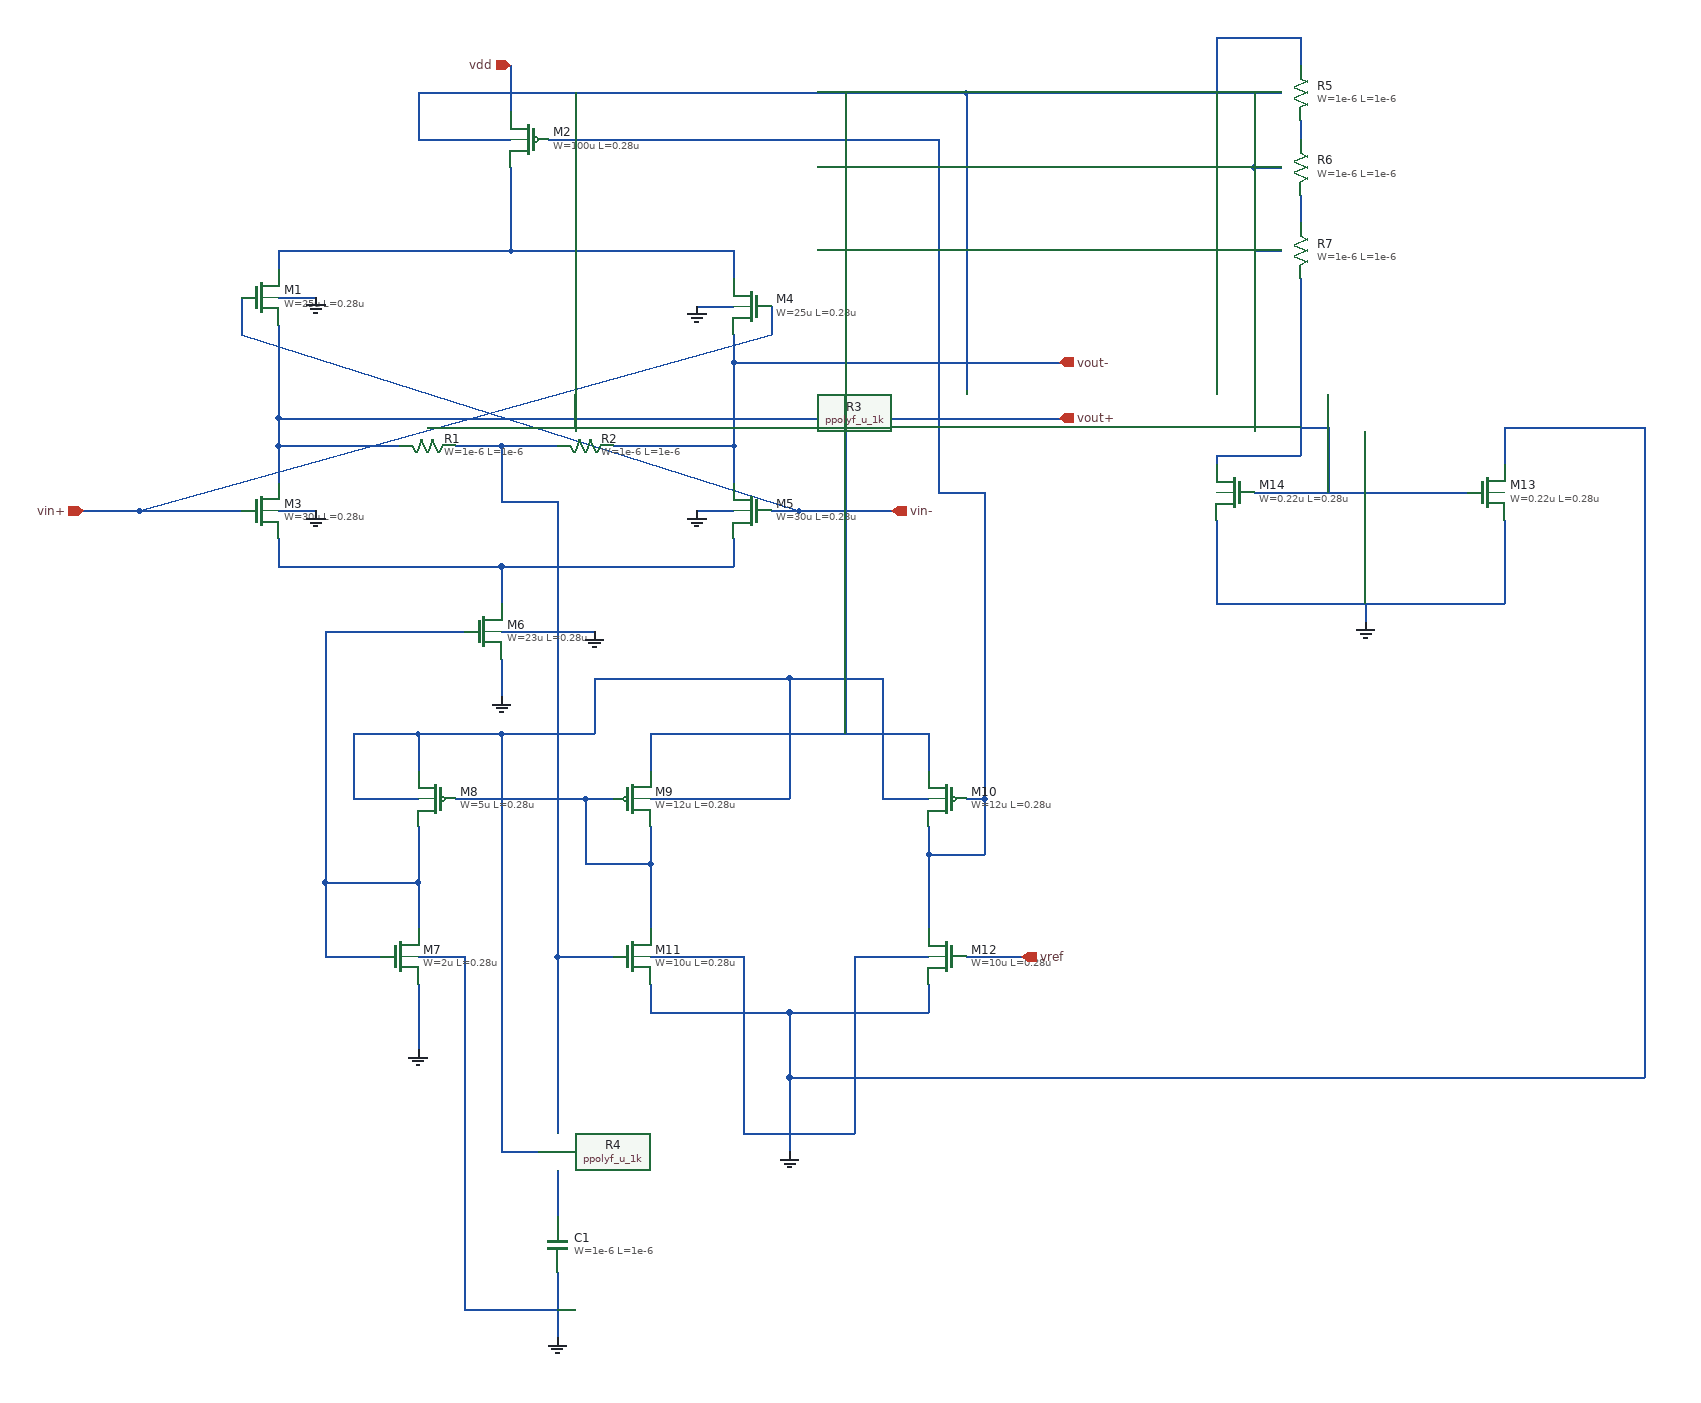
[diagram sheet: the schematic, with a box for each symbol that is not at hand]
v {xschem version=3.4.8RC file_version=1.3}
G {}
K {}
V {}
S {}
F {}
E {}
P 4 1 -660 130 {}
N -940 -600 -940 -560 {lab=vout+}
N -450 -600 -450 -560 {lab=vout-}
N -940 -810 -940 -790 {lab=#net1}
N -690 -810 -450 -810 {lab=#net1}
N -450 -810 -450 -780 {lab=#net1}
N -940 -500 -940 -470 {lab=#net2}
N -700 -470 -450 -470 {lab=#net2}
N -450 -500 -450 -470 {lab=#net2}
N -940 -600 -810 -600 {lab=vout+}
N -700 -600 -640 -600 {lab=#net3}
N -750 -600 -700 -600 {lab=#net3}
N -580 -600 -450 -600 {lab=vout-}
N -450 -690 -100 -690 {lab=vout-}
N -940 -630 -100 -630 {lab=vout+}
N -690 -900 -690 -810 {lab=#net1}
N -690 -1010 -690 -960 {lab=vdd}
N -700 -470 -700 -430 {lab=#net2}
N -700 -370 -700 -330 {lab=0}
N -890 -400 -740 -400 {lab=#net4}
N -890 -130 -890 -50 {lab=#net4}
N -790 -130 -790 -80 {lab=#net4}
N -610 -220 -580 -220 {lab=#net5}
N -540 -290 -540 -250 {lab=vdd}
N -400 -290 -240 -290 {lab=vdd}
N -240 -290 -240 -250 {lab=vdd}
N -540 -150 -540 -80 {lab=#net5}
N -240 -160 -240 -80 {lab=#net6}
N -540 -20 -540 10 {lab=0}
N -390 10 -240 10 {lab=0}
N -240 -20 -240 10 {lab=0}
N -640 -50 -640 20 {lab=#net3}
N -640 -50 -580 -50 {lab=#net3}
N -640 -540 -640 -50 {lab=#net3}
N -700 -540 -640 -540 {lab=#net3}
N -700 -600 -700 -540 {lab=#net3}
N -790 -20 -790 50 {lab=0}
N -200 -50 -140 -50 {lab=vref}
N -390 110 -390 160 {lab=0}
N -890 -50 -830 -50 {lab=#net4}
N -390 10 -390 50 {lab=0}
N -200 -220 -180 -220 {lab=#net6}
N -240 -160 -180 -160 {lab=#net6}
N -180 -220 -180 -160 {lab=#net6}
N -650 -930 -230 -930 {lab=#net6}
N -180 -550 -180 -220 {lab=#net6}
N -230 -550 -180 -550 {lab=#net6}
N -230 -930 -230 -550 {lab=#net6}
N -410 -750 -410 -720 {lab=vin+}
N -1090 -530 -410 -720 {lab=vin+}
N -1090 -530 -980 -530 {lab=vin+}
N -1150 -530 -1090 -530 {lab=vin+}
N -980 -760 -980 -720 {lab=vin-}
N -980 -720 -380 -530 {lab=vin-}
N -410 -530 -380 -530 {lab=vin-}
N -380 -530 -280 -530 {lab=vin-}
N -940 -530 -900 -530 {lab=0}
N -940 -760 -900 -760 {lab=0}
N -490 -750 -450 -750 {lab=0}
N -490 -530 -450 -530 {lab=0}
N -700 -400 -660 -400 {lab=0}
N -790 -290 -790 -250 {lab=vdd}
N -610 -220 -610 -150 {lab=#net5}
N -610 -150 -540 -150 {lab=#net5}
N -890 -130 -790 -130 {lab=#net4}
N -940 -630 -940 -600 {lab=vout+}
N -450 -690 -450 -600 {lab=vout-}
N -450 -720 -450 -690 {lab=vout-}
N -940 -730 -940 -630 {lab=vout+}
N -940 -810 -690 -810 {lab=#net1}
N -940 -470 -700 -470 {lab=#net2}
N -540 -290 -400 -290 {lab=vdd}
N -540 10 -390 10 {lab=0}
N -240 -190 -240 -160 {lab=#net6}
N -750 -220 -610 -220 {lab=#net5}
N -540 -190 -540 -150 {lab=#net5}
N -890 -400 -890 -130 {lab=#net4}
N -790 -190 -790 -130 {lab=#net4}
N -640 20 -640 80 {lab=#net3}
N -640 180 -640 230 {lab=#net7}
N -640 290 -640 360 {lab=0}
N -690 -980 -210 -980 {lab=vdd}
N -210 -980 -200 -980 {lab=vdd}
N -200 -980 -200 -660 {lab=vdd}
N -790 -980 -690 -980 {lab=vdd}
N -790 -980 -790 -930 {lab=vdd}
N -790 -930 -690 -930 {lab=vdd}
N -790 -50 -740 -50 {lab=0}
N -740 -50 -740 330 {lab=0}
N -740 330 -640 330 {lab=0}
N -330 -980 -330 -290 {lab=vdd}
N -540 -220 -390 -220 {lab=vdd}
N -390 -350 -390 -220 {lab=vdd}
N -390 -350 -330 -350 {lab=vdd}
N -290 -220 -240 -220 {lab=vdd}
N -290 -350 -290 -220 {lab=vdd}
N -330 -350 -290 -350 {lab=vdd}
N -700 -290 -700 110 {lab=vdd}
N -700 -290 -600 -290 {lab=vdd}
N -600 -350 -600 -290 {lab=vdd}
N -600 -350 -390 -350 {lab=vdd}
N -540 -50 -440 -50 {lab=0}
N -440 -50 -440 140 {lab=0}
N -440 140 -390 140 {lab=0}
N -390 140 -320 140 {lab=0}
N -320 -50 -320 140 {lab=0}
N -320 -50 -240 -50 {lab=0}
N -790 -290 -700 -290 {lab=vdd}
N -660 -400 -600 -400 {lab=0}
N -860 -220 -790 -220 {lab=vdd}
N -860 -290 -860 -220 {lab=vdd}
N -860 -290 -790 -290 {lab=vdd}
N -200 -980 140 -980 {lab=vdd}
N 70 -1040 70 -980 {lab=vdd}
N 70 -1040 160 -1040 {lab=vdd}
N 160 -1040 160 -1010 {lab=vdd}
N 110 -550 340 -550 {lab=#net8}
N 70 -590 150 -590 {lab=#net8}
N 70 -590 70 -580 {lab=#net8}
N 190 -620 190 -550 {lab=#net8}
N 70 -520 70 -430 {lab=0}
N 70 -430 380 -430 {lab=0}
N 380 -520 380 -430 {lab=0}
N 230 -430 230 -410 {lab=0}
N 380 -620 380 -590 {lab=0}
N 380 -620 520 -620 {lab=0}
N -280 80 530 80 {lab=0}
N -390 80 -280 80 {lab=0}
N -390 80 -390 110 {lab=0}
N -390 50 -390 70 {lab=0}
N -390 70 -390 80 {lab=0}
N 380 -590 380 -580 {lab=0}
N 160 -950 160 -930 {lab=#net9}
N 160 -870 160 -840 {lab=#net10}
N 160 -780 160 -640 {lab=#net8}
N 110 -900 140 -900 {lab=vdd}
N 110 -980 110 -900 {lab=vdd}
N 120 -810 140 -810 {lab=vdd}
N 110 -900 110 -810 {lab=vdd}
N 110 -810 120 -810 {lab=vdd}
N 150 -590 160 -590 {lab=#net8}
N 160 -640 160 -590 {lab=#net8}
N 160 -620 190 -620 {lab=#net8}
N 520 -620 530 -620 {lab=0}
N 530 -620 530 80 {lab=0}
N -640 80 -640 140 {lab=#net3}
N -700 110 -700 160 {lab=vdd}
N -700 160 -660 160 {lab=vdd}
N -780 -620 -610 -620 {lab=vdd}
N -620 -980 -620 -620 {lab=vdd}
C {symbols/nfet_03v3.sym} -960 -760 0 0 {name=M1
L=0.28u
W=25u
nf=1
m=2
ad="'int((nf+1)/2) * W/nf * 0.18u'"
pd="'2*int((nf+1)/2) * (W/nf + 0.18u)'"
as="'int((nf+2)/2) * W/nf * 0.18u'"
ps="'2*int((nf+2)/2) * (W/nf + 0.18u)'"
nrd="'0.18u / W'" nrs="'0.18u / W'"
sa=0 sb=0 sd=0
model=nfet_03v3
spiceprefix=X
}
C {symbols/pfet_03v3.sym} -670 -930 0 1 {name=M2
L=0.28u
W=100u
nf=1
m=1
ad="'int((nf+1)/2) * W/nf * 0.18u'"
pd="'2*int((nf+1)/2) * (W/nf + 0.18u)'"
as="'int((nf+2)/2) * W/nf * 0.18u'"
ps="'2*int((nf+2)/2) * (W/nf + 0.18u)'"
nrd="'0.18u / W'" nrs="'0.18u / W'"
sa=0 sb=0 sd=0
model=pfet_03v3
spiceprefix=X
}
C {symbols/nfet_03v3.sym} -960 -530 0 0 {name=M3
L=0.28u
W=30u
nf=1
m=2
ad="'int((nf+1)/2) * W/nf * 0.18u'"
pd="'2*int((nf+1)/2) * (W/nf + 0.18u)'"
as="'int((nf+2)/2) * W/nf * 0.18u'"
ps="'2*int((nf+2)/2) * (W/nf + 0.18u)'"
nrd="'0.18u / W'" nrs="'0.18u / W'"
sa=0 sb=0 sd=0
model=nfet_03v3
spiceprefix=X
}
C {symbols/nfet_03v3.sym} -430 -750 0 1 {name=M4
L=0.28u
W=25u
nf=1
m=2
ad="'int((nf+1)/2) * W/nf * 0.18u'"
pd="'2*int((nf+1)/2) * (W/nf + 0.18u)'"
as="'int((nf+2)/2) * W/nf * 0.18u'"
ps="'2*int((nf+2)/2) * (W/nf + 0.18u)'"
nrd="'0.18u / W'" nrs="'0.18u / W'"
sa=0 sb=0 sd=0
model=nfet_03v3
spiceprefix=X
}
C {symbols/nfet_03v3.sym} -430 -530 0 1 {name=M5
L=0.28u
W=30u
nf=1
m=2
ad="'int((nf+1)/2) * W/nf * 0.18u'"
pd="'2*int((nf+1)/2) * (W/nf + 0.18u)'"
as="'int((nf+2)/2) * W/nf * 0.18u'"
ps="'2*int((nf+2)/2) * (W/nf + 0.18u)'"
nrd="'0.18u / W'" nrs="'0.18u / W'"
sa=0 sb=0 sd=0
model=nfet_03v3
spiceprefix=X
}
C {symbols/nfet_03v3.sym} -720 -400 0 0 {name=M6
L=0.28u
W=23u
nf=1
m=2
ad="'int((nf+1)/2) * W/nf * 0.18u'"
pd="'2*int((nf+1)/2) * (W/nf + 0.18u)'"
as="'int((nf+2)/2) * W/nf * 0.18u'"
ps="'2*int((nf+2)/2) * (W/nf + 0.18u)'"
nrd="'0.18u / W'" nrs="'0.18u / W'"
sa=0 sb=0 sd=0
model=nfet_03v3
spiceprefix=X
}
C {symbols/nfet_03v3.sym} -810 -50 0 0 {name=M7
L=0.28u
W=2u
nf=1
m=1
ad="'int((nf+1)/2) * W/nf * 0.18u'"
pd="'2*int((nf+1)/2) * (W/nf + 0.18u)'"
as="'int((nf+2)/2) * W/nf * 0.18u'"
ps="'2*int((nf+2)/2) * (W/nf + 0.18u)'"
nrd="'0.18u / W'" nrs="'0.18u / W'"
sa=0 sb=0 sd=0
model=nfet_03v3
spiceprefix=X
}
C {symbols/pfet_03v3.sym} -770 -220 0 1 {name=M8
L=0.28u
W=5u
nf=1
m=1
ad="'int((nf+1)/2) * W/nf * 0.18u'"
pd="'2*int((nf+1)/2) * (W/nf + 0.18u)'"
as="'int((nf+2)/2) * W/nf * 0.18u'"
ps="'2*int((nf+2)/2) * (W/nf + 0.18u)'"
nrd="'0.18u / W'" nrs="'0.18u / W'"
sa=0 sb=0 sd=0
model=pfet_03v3
spiceprefix=X
}
C {symbols/pfet_03v3.sym} -560 -220 0 0 {name=M9
L=0.28u
W=12u
nf=1
m=1
ad="'int((nf+1)/2) * W/nf * 0.18u'"
pd="'2*int((nf+1)/2) * (W/nf + 0.18u)'"
as="'int((nf+2)/2) * W/nf * 0.18u'"
ps="'2*int((nf+2)/2) * (W/nf + 0.18u)'"
nrd="'0.18u / W'" nrs="'0.18u / W'"
sa=0 sb=0 sd=0
model=pfet_03v3
spiceprefix=X
}
C {symbols/pfet_03v3.sym} -220 -220 0 1 {name=M10
L=0.28u
W=12u
nf=1
m=1
ad="'int((nf+1)/2) * W/nf * 0.18u'"
pd="'2*int((nf+1)/2) * (W/nf + 0.18u)'"
as="'int((nf+2)/2) * W/nf * 0.18u'"
ps="'2*int((nf+2)/2) * (W/nf + 0.18u)'"
nrd="'0.18u / W'" nrs="'0.18u / W'"
sa=0 sb=0 sd=0
model=pfet_03v3
spiceprefix=X
}
C {symbols/nfet_03v3.sym} -560 -50 0 0 {name=M11
L=0.28u
W=10u
nf=1
m=1
ad="'int((nf+1)/2) * W/nf * 0.18u'"
pd="'2*int((nf+1)/2) * (W/nf + 0.18u)'"
as="'int((nf+2)/2) * W/nf * 0.18u'"
ps="'2*int((nf+2)/2) * (W/nf + 0.18u)'"
nrd="'0.18u / W'" nrs="'0.18u / W'"
sa=0 sb=0 sd=0
model=nfet_03v3
spiceprefix=X
}
C {symbols/nfet_03v3.sym} -220 -50 0 1 {name=M12
L=0.28u
W=10u
nf=1
m=1
ad="'int((nf+1)/2) * W/nf * 0.18u'"
pd="'2*int((nf+1)/2) * (W/nf + 0.18u)'"
as="'int((nf+2)/2) * W/nf * 0.18u'"
ps="'2*int((nf+2)/2) * (W/nf + 0.18u)'"
nrd="'0.18u / W'" nrs="'0.18u / W'"
sa=0 sb=0 sd=0
model=nfet_03v3
spiceprefix=X
}
C {ipin.sym} -1150 -530 0 0 {name=p14 lab=vin+}
C {ipin.sym} -280 -530 0 1 {name=p15 lab=vin-}
C {opin.sym} -100 -690 0 0 {name=p20 lab=vout-}
C {opin.sym} -100 -630 0 0 {name=p21 lab=vout+}
C {symbols/cap_mim_2f0fF.sym} -640 260 0 0 {name=C1
W=1e-6
L=1e-6
model=cap_mim_2f0fF
spiceprefix=X
m=50}
C {symbols/ppolyf_u_1k.sym} -780 -600 1 0 {name=R1
W=1e-6
L=1e-6
model=ppolyf_u_1k
spiceprefix=X
m=1}
C {symbols/ppolyf_u_1k.sym} -610 -600 1 0 {name=R2
W=1e-6
L=1e-6
model=ppolyf_u_1k
spiceprefix=X
m=1}
C {symbols/ppolyf_u_1k.sym} -180 -660 0 0 {name=R3
W=1e-6
L=1e-6
model=ppolyf_u_1k
spiceprefix=X
m=12}
C {ipin.sym} -140 -50 0 1 {name=p9 lab=vref}
C {ipin.sym} -690 -1010 0 0 {name=p16 lab=vdd}
C {gnd.sym} -390 160 0 0 {name=l1 lab=0}
C {gnd.sym} -790 50 0 0 {name=l2 lab=0}
C {gnd.sym} -640 360 0 0 {name=l3 lab=0}
C {gnd.sym} -700 -330 0 0 {name=l5 lab=0}
C {gnd.sym} -900 -530 3 0 {name=l6 lab=0}
C {gnd.sym} -900 -760 3 0 {name=l7 lab=0}
C {gnd.sym} -490 -750 1 1 {name=l8 lab=0}
C {gnd.sym} -490 -530 1 1 {name=l9 lab=0}
C {gnd.sym} -600 -400 3 0 {name=l10 lab=0}
C {symbols/nfet_03v3.sym} 360 -550 0 0 {name=M13
L=0.28u
W=0.22u
nf=1
m=1
ad="'int((nf+1)/2) * W/nf * 0.18u'"
pd="'2*int((nf+1)/2) * (W/nf + 0.18u)'"
as="'int((nf+2)/2) * W/nf * 0.18u'"
ps="'2*int((nf+2)/2) * (W/nf + 0.18u)'"
nrd="'0.18u / W'" nrs="'0.18u / W'"
sa=0 sb=0 sd=0
model=nfet_03v3
spiceprefix=X
}
C {symbols/nfet_03v3.sym} 90 -550 0 1 {name=M14
L=0.28u
W=0.22u
nf=1
m=1
ad="'int((nf+1)/2) * W/nf * 0.18u'"
pd="'2*int((nf+1)/2) * (W/nf + 0.18u)'"
as="'int((nf+2)/2) * W/nf * 0.18u'"
ps="'2*int((nf+2)/2) * (W/nf + 0.18u)'"
nrd="'0.18u / W'" nrs="'0.18u / W'"
sa=0 sb=0 sd=0
model=nfet_03v3
spiceprefix=X
}
C {gnd.sym} 230 -410 0 1 {name=l4 lab=0}
C {symbols/ppolyf_u_3k.sym} 160 -980 0 0 {name=R5
W=1e-6
L=1e-6
model=ppolyf_u_3k
spiceprefix=X
m=1}
C {symbols/ppolyf_u_3k.sym} 160 -900 0 0 {name=R6
W=1e-6
L=1e-6
model=ppolyf_u_3k
spiceprefix=X
m=1}
C {symbols/ppolyf_u_1k.sym} -640 160 0 0 {name=R4
W=1e-6
L=1e-6
model=ppolyf_u_1k
spiceprefix=X
m=1}
C {symbols/ppolyf_u_3k.sym} 160 -810 0 0 {name=R7
W=1e-6
L=1e-6
model=ppolyf_u_3k
spiceprefix=X
m=1}
